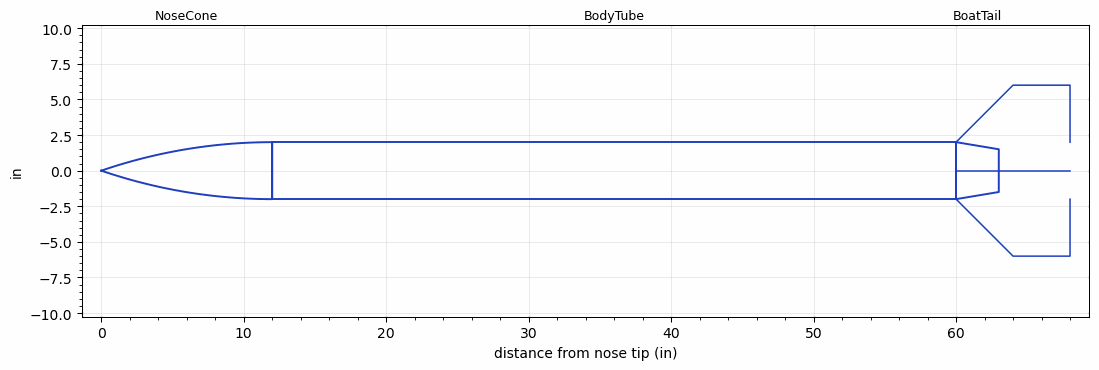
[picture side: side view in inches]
<RASAeroDocument>
 <FileVersion>2</FileVersion>
 <RocketDesign>
  <NoseCone>
   <Length>12.0</Length>
   <Diameter>4.0</Diameter>
   <Shape>Tangent Ogive</Shape>
   <Location>0</Location>
  </NoseCone>
  <BodyTube>
   <Length>48.0</Length>
   <Diameter>4.0</Diameter>
   <LaunchLugDiameter>0.5</LaunchLugDiameter>
   <LaunchLugLength>2.0</LaunchLugLength>
   <RailGuideDiameter>0.5</RailGuideDiameter>
   <RailGuideHeight>0.5</RailGuideHeight>
   <LaunchShoeArea>0.75</LaunchShoeArea>
   <Location>12.0</Location>
   <Fin>
    <Count>4</Count>
    <Chord>8.0</Chord>
    <Span>4.0</Span>
    <SweepDistance>4.0</SweepDistance>
    <TipChord>4.0</TipChord>
    <Thickness>0.125</Thickness>
    <Location>0.0</Location>
    <AirfoilSection>Hexagonal</AirfoilSection>
    <FX1>2.0</FX1>
    <FX3>2.0</FX3>
   </Fin>
   <Protuberance>
    <StreamlinedNoBaseDrag>0.6</StreamlinedNoBaseDrag>
    <StreamlinedWithBaseDrag>0.4</StreamlinedWithBaseDrag>
    <InclinedPlate1Angle>30.0</InclinedPlate1Angle>
    <InclinedPlate1FrontalArea>0.3</InclinedPlate1FrontalArea>
    <InclinedPlate2Angle>60.0</InclinedPlate2Angle>
    <InclinedPlate2FrontalArea>0.2</InclinedPlate2FrontalArea>
   </Protuberance>
  </BodyTube>
  <BoatTail>
   <Length>3.0</Length>
   <Diameter>4.0</Diameter>
   <RearDiameter>3.0</RearDiameter>
   <Location>60.0</Location>
  </BoatTail>
  <Surface>Smooth (Zero Roughness)</Surface>
  <ModifiedBarrowman>False</ModifiedBarrowman>
  <Turbulence>False</Turbulence>
  <UseBooster1>False</UseBooster1>
  <UseBooster2>False</UseBooster2>
  <Comments>Oracle case: combo_all_protuberances</Comments>
 </RocketDesign>
 <LaunchSite>
  <Altitude>0</Altitude>
  <Pressure>0</Pressure>
  <RodAngle>0</RodAngle>
  <RodLength>10</RodLength>
  <Temperature>59</Temperature>
  <WindSpeed>0</WindSpeed>
 </LaunchSite>
 <Recovery>
  <Altitude1>1000</Altitude1>
  <DeviceType1>None</DeviceType1>
  <Event1>False</Event1>
  <Size1>1</Size1>
  <EventType1>None</EventType1>
  <CD1>1.33</CD1>
  <Altitude2>1000</Altitude2>
  <DeviceType2>None</DeviceType2>
  <Event2>False</Event2>
  <Size2>1</Size2>
  <EventType2>None</EventType2>
  <CD2>1.33</CD2>
 </Recovery>
</RASAeroDocument>
